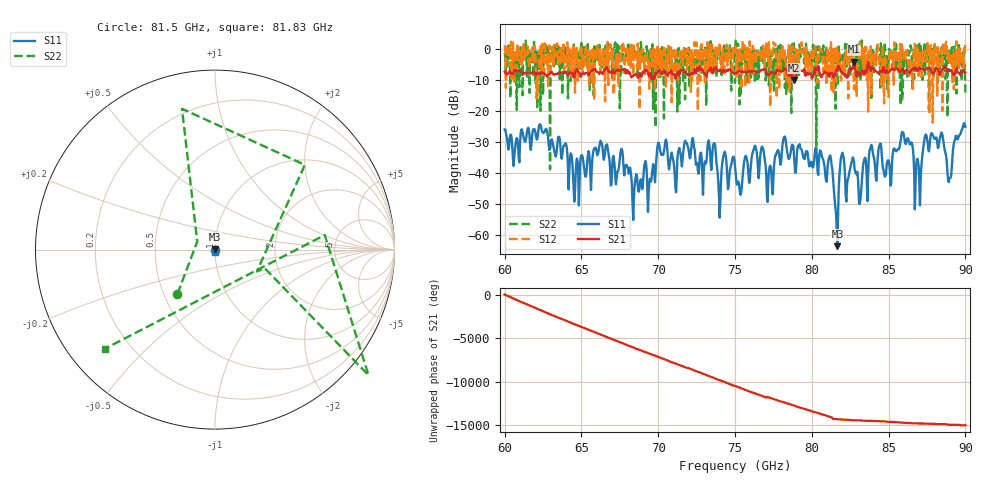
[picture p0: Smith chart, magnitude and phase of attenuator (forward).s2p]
!Created with skrf (http://scikit-rf.org).
# GHz S RI R 50.0
!freq ReS11 ImS11 ReS21 ImS21 ReS12 ImS12 ReS22 ImS22
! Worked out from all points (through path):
!   721 points, 60 GHz to 90 GHz, reference 50 ohm
!   highest |S21| = -4.05 dB at 82.75 GHz (marker M1); lowest = -10.0 dB at 78.83 GHz (marker M2)
!   lowest |S11| = -63.8 dB at 81.67 GHz (marker M3), VSWR 1.00, Z = 50 + j0.0605 ohm
!   |S11| at or under -10 dB: start of sweep to end of sweep
!   |S22| runs from -38.9 to 2.8 dB; largest |S21 - S12| = 1.8
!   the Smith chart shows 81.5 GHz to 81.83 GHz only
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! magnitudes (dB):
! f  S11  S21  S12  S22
! 60 GHz  -26.0  -7.3  1.3  -1.2
! 65 GHz  -34.3  -8.5  0.7  2.0
! 67.58 GHz  -32.4  -6.7  0.9  -8.7
! 68.42 GHz  -48.4  -8.5  1.2  -2.2
! 69.71 GHz  -37.7  -9.7  -1.4  -10.5
! 70 GHz  -30.3  -7.3  -9.7  -7.9
! 75 GHz  -37.8  -7.7  0.1  -10.9
! 78.83 GHz  -33.7  -10.0  -9.2  2.4
! 80 GHz  -37.0  -8.6  -9.7  -7.5
! 81.21 GHz  -34.4  -7.7  -8.6  0.5
! 81.67 GHz  -63.8  -6.3  -6.2  -11.6
! 81.96 GHz  -34.0  -7.3  -4.5  -1.4
! 82.75 GHz  -36.8  -4.1  -13.0  -3.1
! 83.12 GHz  -50.0  -8.3  2.3  -3.2
! 83.88 GHz  -31.0  -6.5  -14.4  -15.8
! 85 GHz  -36.1  -7.4  -15.4  -5.7
! 85.92 GHz  -26.9  -6.4  -1.0  -14.7
! 87.04 GHz  -50.6  -6.5  -1.6  -7.0
! 87.38 GHz  -28.0  -6.7  -0.5  -8.2
! 88.42 GHz  -27.2  -7.1  -0.7  -1.0
! 88.96 GHz  -41.7  -6.6  -5.0  -1.9
! 90 GHz  -25.1  -7.5  2.5  -14.0
